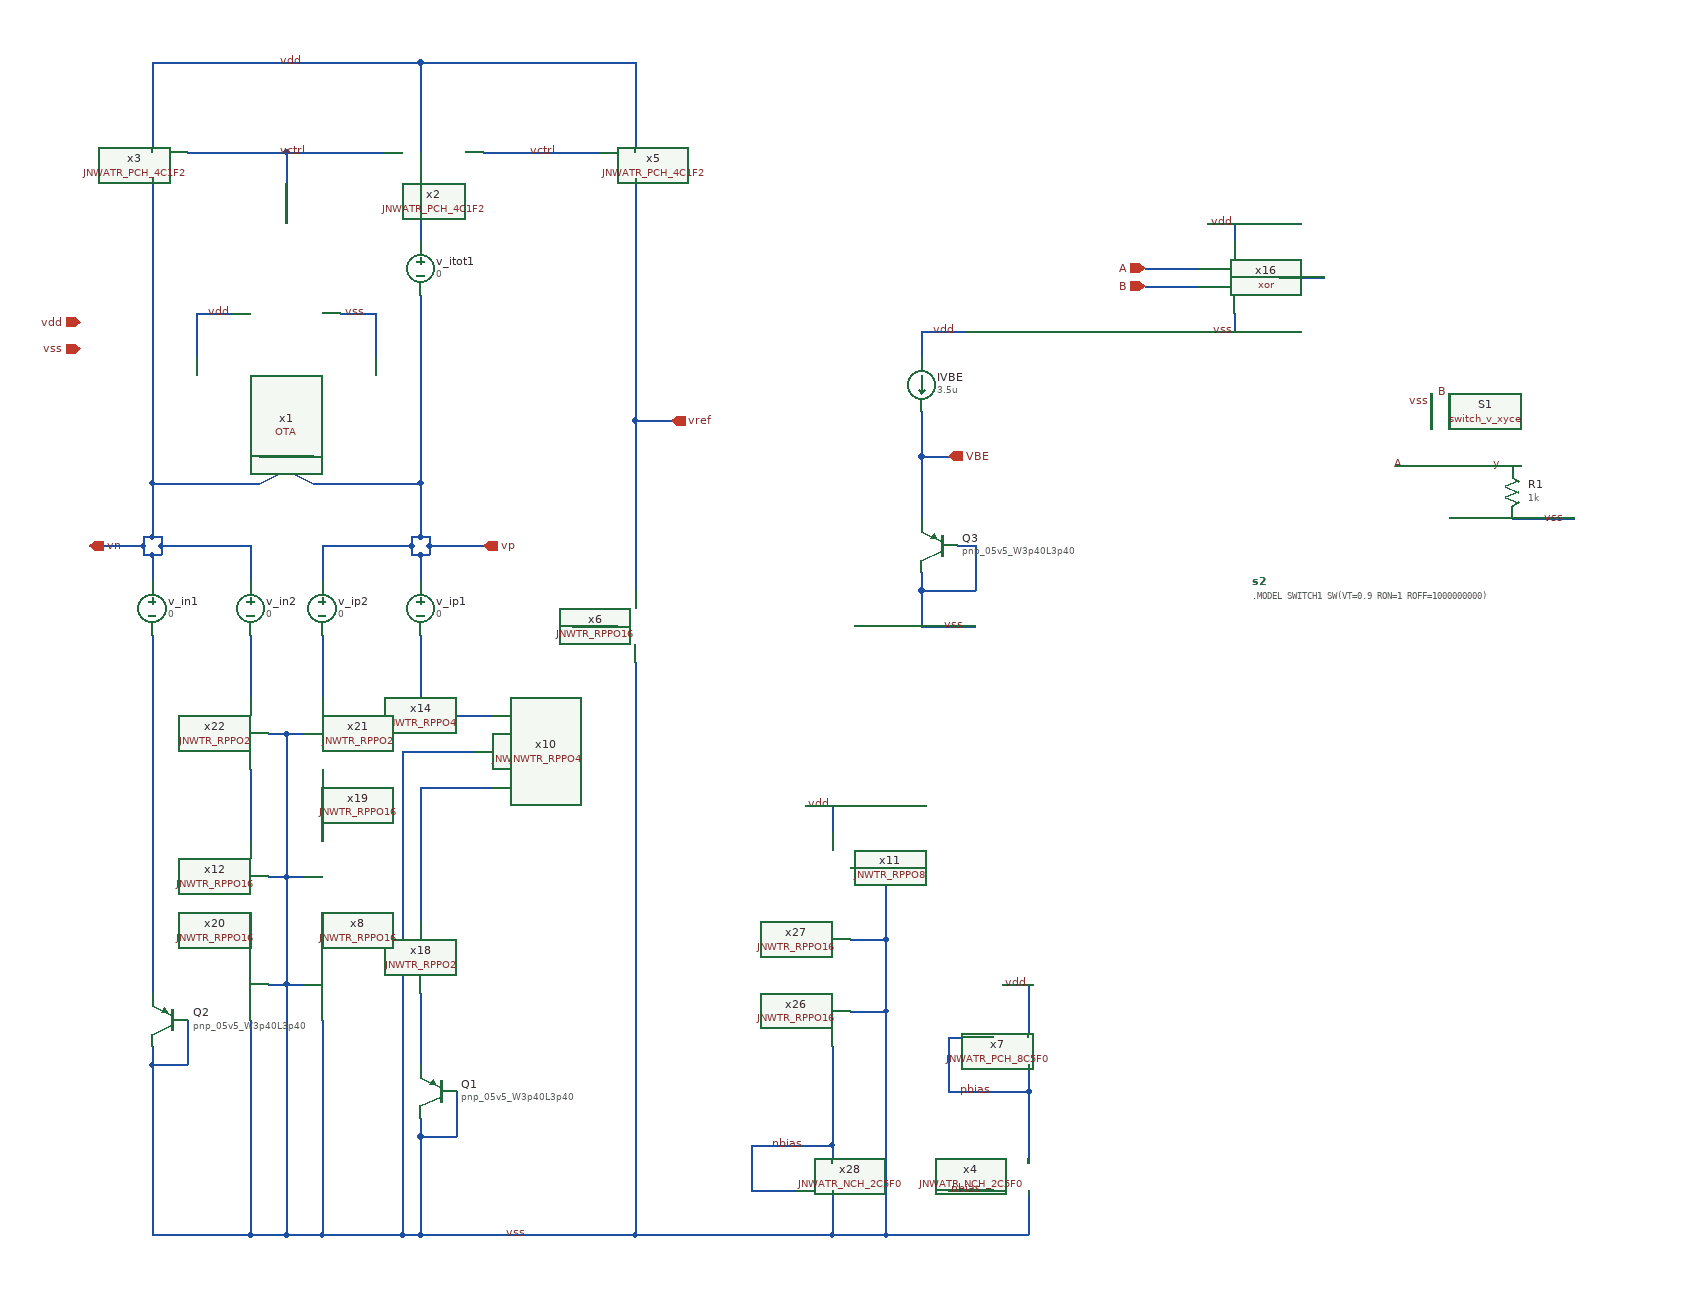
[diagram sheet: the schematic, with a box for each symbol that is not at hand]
v {xschem version=3.4.5 file_version=1.2
}
G {}
K {}
V {}
S {}
E {}
N 870 -120 960 -120 {
lab=nbias}
N 960 -120 960 -100 {
lab=nbias}
N 1180 -210 1180 -180 {
lab=pbias}
N 1090 -180 1180 -180 {
lab=pbias}
N 1090 -240 1090 -180 {
lab=pbias}
N 1090 -240 1140 -240 {
lab=pbias}
N 1180 -300 1180 -240 {
lab=vdd}
N 960 -70 960 -20 {
lab=vss}
N 930 -500 960 -500 {
lab=vdd}
N 1020 -270 1020 -20 {
lab=vss}
N 980 -270 1020 -270 {
lab=vss}
N 1020 -350 1020 -270 {
lab=vss}
N 980 -350 1020 -350 {
lab=vss}
N 1020 -430 1020 -350 {
lab=vss}
N 980 -430 1020 -430 {
lab=vss}
N 960 -500 960 -470 {
lab=vdd}
N 1090 -70 1140 -70 {
lab=nbias}
N 1020 -20 1180 -20 {
lab=vss}
N 1150 -300 1180 -300 {
lab=vdd}
N 870 -120 870 -70 {
lab=nbias}
N 870 -70 920 -70 {
lab=nbias}
N 1180 -70 1180 -20 {
lab=vss}
N 1180 -180 1180 -100 {
lab=pbias}
N 960 -230 960 -120 {
lab=nbias}
N 490 -790 490 -780 {
lab=vp}
N 500 -800 510 -800 {
lab=vp}
N 210 -790 210 -780 {
lab=vn}
N 200 -800 210 -800 {
lab=vn}
N 510 -790 510 -780 {
lab=vp}
N 210 -800 210 -790 {
lab=vn}
N 490 -800 490 -790 {
lab=vp}
N 390 -790 490 -790 {
lab=vp}
N 200 -780 210 -780 {
lab=vn}
N 210 -790 310 -790 {
lab=vn}
N 190 -790 190 -780 {
lab=vn}
N 240 -260 240 -210 {
lab=vss}
N 200 -210 240 -210 {
lab=vss}
N 200 -230 200 -210 {
lab=vss}
N 540 -180 540 -130 {
lab=vss}
N 500 -130 540 -130 {
lab=vss}
N 500 -150 500 -130 {
lab=vss}
N 500 -780 510 -780 {
lab=vp}
N 380 -860 500 -860 {
lab=vp}
N 200 -860 200 -800 {
lab=vn}
N 190 -800 200 -800 {
lab=vn}
N 500 -860 500 -800 {
lab=vp}
N 490 -800 500 -800 {
lab=vp}
N 200 -1200 200 -860 {
lab=vn}
N 200 -860 320 -860 {
lab=vn}
N 350 -1230 350 -1150 {
lab=vctrl}
N 350 -1230 460 -1230 {
lab=vctrl}
N 240 -1230 350 -1230 {
lab=vctrl}
N 200 -1330 200 -1230 {
lab=vdd}
N 200 -1330 500 -1330 {
lab=vdd}
N 740 -1330 740 -1230 {
lab=vdd}
N 500 -1330 740 -1330 {
lab=vdd}
N 500 -1330 500 -1230 {
lab=vdd}
N 740 -930 740 -740 {
lab=vref}
N 510 -790 570 -790 {
lab=vp}
N 510 -800 510 -790 {
lab=vp}
N 130 -790 190 -790 {
lab=vn}
N 190 -800 190 -790 {
lab=vn}
N 740 -930 780 -930 {
lab=vref}
N 740 -1200 740 -930 {
lab=vref}
N 570 -1230 700 -1230 {
lab=vctrl}
N 500 -130 500 -20 {
lab=vss}
N 200 -210 200 -20 {
lab=vss}
N 500 -20 740 -20 {
lab=vss}
N 670 -700 720 -700 {
lab=vss}
N 740 -660 740 -20 {
lab=vss}
N 960 -20 1020 -20 {
lab=vss}
N 740 -20 960 -20 {
lab=vss}
N 480 -20 500 -20 {
lab=vss}
N 500 -1200 500 -1130 {
lab=#net1}
N 500 -780 500 -750 {
lab=vp}
N 490 -780 500 -780 {
lab=vp}
N 390 -790 390 -750 {
lab=vp}
N 200 -780 200 -750 {
lab=vn}
N 190 -780 200 -780 {
lab=vn}
N 200 -690 200 -290 {
lab=#net2}
N 310 -790 310 -750 {
lab=vn}
N 1060 -890 1060 -820 {
lab=VBE}
N 1060 -740 1060 -700 {
lab=vss}
N 1060 -700 1120 -700 {
lab=vss}
N 1060 -1030 1060 -1000 {
lab=vdd}
N 1060 -1030 1110 -1030 {
lab=vdd}
N 1060 -890 1090 -890 {
lab=VBE}
N 1060 -940 1060 -890 {
lab=VBE}
N 1100 -790 1120 -790 {
lab=vss}
N 1120 -790 1120 -740 {
lab=vss}
N 1060 -740 1120 -740 {
lab=vss}
N 1060 -760 1060 -740 {
lab=vss}
N 1310 -1100 1370 -1100 {
lab=A}
N 1310 -1080 1370 -1080 {
lab=B}
N 1410 -1150 1410 -1130 {
lab=vdd}
N 1380 -1150 1410 -1150 {
lab=vdd}
N 1410 -1050 1410 -1030 {
lab=vss}
N 1380 -1030 1410 -1030 {
lab=vss}
N 1460 -1090 1510 -1090 {
lab=#net3}
N 500 -520 500 -370 {
lab=#net4}
N 350 -300 370 -300 {
lab=vss}
N 330 -300 350 -300 {
lab=vss}
N 310 -380 310 -340 {
lab=#net5}
N 390 -380 390 -340 {
lab=#net6}
N 350 -420 370 -420 {
lab=vss}
N 330 -420 350 -420 {
lab=vss}
N 350 -420 350 -300 {
lab=vss}
N 350 -580 370 -580 {
lab=vss}
N 350 -580 350 -420 {
lab=vss}
N 330 -580 350 -580 {
lab=vss}
N 390 -540 390 -460 {
lab=#net7}
N 310 -540 310 -460 {
lab=#net8}
N 500 -520 580 -520 {
lab=#net4}
N 500 -600 580 -600 {
lab=#net9}
N 480 -560 560 -560 {
lab=vss}
N 310 -690 310 -620 {
lab=#net10}
N 390 -690 390 -620 {
lab=#net11}
N 500 -690 500 -600 {
lab=#net9}
N 500 -290 500 -210 {
lab=#net12}
N 480 -560 480 -20 {
lab=vss}
N 390 -20 480 -20 {
lab=vss}
N 350 -300 350 -20 {
lab=vss}
N 310 -260 310 -20 {
lab=vss}
N 200 -20 310 -20 {
lab=vss}
N 390 -260 390 -20 {
lab=vss}
N 350 -20 390 -20 {
lab=vss}
N 310 -20 350 -20 {
lab=vss}
N 500 -1070 500 -860 {
lab=vp}
N 320 -860 380 -890 {
lab=vn}
N 320 -890 380 -860 {
lab=vp}
N 250 -1050 250 -1000 {
lab=vdd}
N 250 -1050 290 -1050 {
lab=vdd}
N 450 -1050 450 -1000 {
lab=vss}
N 410 -1050 450 -1050 {
lab=vss}
N 1680 -880 1720 -880 {
lab=y}
N 1630 -960 1630 -920 {
lab=vss}
N 1650 -960 1650 -920 {
lab=B}
N 1590 -880 1620 -880 {
lab=A}
N 1720 -820 1790 -820 {
lab=vss}
C {devices/ipin.sym} 120 -1010 0 0 {name=p4 lab=vss}
C {devices/ipin.sym} 120 -1040 0 0 {name=p5 lab=vdd}
C {devices/lab_wire.sym} 1140 -180 0 0 {name=p32 sig_type=std_logic lab=pbias}
C {devices/lab_wire.sym} 960 -500 0 0 {name=p34 sig_type=std_logic lab=vdd}
C {JNW_ATR_SKY130A/JNWATR_PCH_8C5F0.sym} 1140 -240 0 0 {name=x7 }
C {JNW_ATR_SKY130A/JNWATR_NCH_2C5F0.sym} 920 -70 0 0 {name=x28 }
C {devices/lab_wire.sym} 930 -120 0 0 {name=p12 sig_type=std_logic lab=nbias}
C {devices/lab_wire.sym} 1180 -300 0 0 {name=p13 sig_type=std_logic lab=vdd}
C {JNW_ATR_SKY130A/JNWATR_NCH_2C5F0.sym} 1140 -70 0 0 {name=x4 }
C {devices/lab_wire.sym} 1130 -70 0 0 {name=p14 sig_type=std_logic lab=nbias}
C {JNW_TR_SKY130A/JNWTR_RPPO16.sym} 960 -230 3 0 {name=x26 }
C {JNW_TR_SKY130A/JNWTR_RPPO16.sym} 960 -310 3 0 {name=x27 }
C {JNW_TR_SKY130A/JNWTR_RPPO8.sym} 960 -390 3 0 {name=x11 }
C {sky130_fd_pr/pnp_05v5.sym} 520 -180 0 1 {name=Q1
model=pnp_05v5_W3p40L3p40
m=8
spiceprefix=X
}
C {sky130_fd_pr/pnp_05v5.sym} 220 -260 0 1 {name=Q2
model=pnp_05v5_W3p40L3p40
m=1
spiceprefix=X
}
C {devices/lab_wire.sym} 340 -1330 0 1 {name=p29 sig_type=std_logic lab=vdd

}
C {devices/opin.sym} 130 -790 2 0 {name=p44 lab=vn}
C {JNW_ATR_SKY130A/JNWATR_PCH_4C1F2.sym} 460 -1230 0 0 {name=x2 }
C {JNW_ATR_SKY130A/JNWATR_PCH_4C1F2.sym} 240 -1230 0 1 {name=x3 }
C {JNW_ATR_SKY130A/JNWATR_PCH_4C1F2.sym} 700 -1230 0 0 {name=x5 }
C {devices/lab_wire.sym} 340 -1230 0 1 {name=p8 sig_type=std_logic lab=vctrl

}
C {devices/lab_wire.sym} 620 -1230 0 1 {name=p9 sig_type=std_logic lab=vctrl

}
C {devices/lab_wire.sym} 620 -20 0 0 {name=p3 sig_type=std_logic lab=vss
}
C {devices/opin.sym} 570 -790 0 0 {name=p7 lab=vp}
C {devices/opin.sym} 780 -930 0 0 {name=p10 lab=vref}
C {devices/lab_wire.sym} 700 -700 0 0 {name=p11 sig_type=std_logic lab=vss
}
C {JNW_TR_SKY130A/JNWTR_RPPO16.sym} 740 -740 1 0 {name=x6 }
C {devices/vsource.sym} 500 -1100 0 0 {name=v_itot1 value=0 savecurrent=true}
C {devices/vsource.sym} 500 -720 0 0 {name=v_ip1 value=0 savecurrent=true}
C {devices/vsource.sym} 390 -720 0 0 {name=v_ip2 value=0 savecurrent=true}
C {devices/vsource.sym} 200 -720 0 0 {name=v_in1 value=0 savecurrent=true}
C {devices/vsource.sym} 310 -720 0 0 {name=v_in2 value=0 savecurrent=true}
C {devices/isource.sym} 1060 -970 0 0 {name=IVBE value=3.5u}
C {devices/lab_wire.sym} 1100 -1030 0 0 {name=p15 sig_type=std_logic lab=vdd}
C {devices/lab_wire.sym} 1110 -700 0 0 {name=p16 sig_type=std_logic lab=vss
}
C {devices/opin.sym} 1090 -890 0 0 {name=p17 lab=VBE}
C {sky130_fd_pr/pnp_05v5.sym} 1080 -790 0 1 {name=Q3
model=pnp_05v5_W3p40L3p40
m=8
spiceprefix=X
}
C {devices/ipin.sym} 1310 -1080 0 0 {name=p18 lab=B}
C {devices/ipin.sym} 1310 -1100 0 0 {name=p19 lab=A}
C {JNW_AVV_SKY130A/xor.sym} 1410 -1090 0 0 {name=x16}
C {devices/lab_wire.sym} 1410 -1150 0 0 {name=p20 sig_type=std_logic lab=vdd}
C {devices/lab_wire.sym} 1410 -1030 0 0 {name=p21 sig_type=std_logic lab=vss
}
C {JNW_TR_SKY130A/JNWTR_RPPO2.sym} 500 -370 1 0 {name=x18 }
C {JNW_TR_SKY130A/JNWTR_RPPO16.sym} 390 -340 1 0 {name=x8 }
C {JNW_TR_SKY130A/JNWTR_RPPO16.sym} 310 -340 3 1 {name=x20 }
C {JNW_TR_SKY130A/JNWTR_RPPO4.sym} 540 -600 1 0 {name=x9 }
C {JNW_TR_SKY130A/JNWTR_RPPO4.sym} 500 -600 1 0 {name=x14 }
C {JNW_TR_SKY130A/JNWTR_RPPO4.sym} 580 -600 1 0 {name=x10 }
C {JNW_TR_SKY130A/JNWTR_RPPO16.sym} 310 -460 3 1 {name=x12 }
C {JNW_TR_SKY130A/JNWTR_RPPO16.sym} 390 -460 1 0 {name=x19 }
C {JNW_TR_SKY130A/JNWTR_RPPO2.sym} 390 -620 1 0 {name=x21 }
C {JNW_TR_SKY130A/JNWTR_RPPO2.sym} 310 -540 3 0 {name=x22 }
C {JNW_AVV_SKY130A/OTA.sym} 350 -1000 3 0 {name=x1}
C {devices/lab_wire.sym} 260 -1050 0 1 {name=p1 sig_type=std_logic lab=vdd

}
C {devices/lab_wire.sym} 440 -1050 0 0 {name=p2 sig_type=std_logic lab=vss
}
C {devices/lab_wire.sym} 1630 -950 0 0 {name=p6 sig_type=std_logic lab=vss
}
C {devices/lab_wire.sym} 1600 -880 0 0 {name=p23 sig_type=std_logic lab=A
}
C {devices/lab_wire.sym} 1650 -960 0 0 {name=p24 sig_type=std_logic lab=B
}
C {devices/lab_wire.sym} 1710 -880 0 0 {name=p25 sig_type=std_logic lab=y
}
C {devices/switch_v_xyce.sym} 1650 -880 1 0 {.MODEL SWITCH1 SW(VT=0.5 VH=0.01 RON=0.01 ROFF=10000000)

name=S1 model=SWITCH1 state=OFF

}
C {devices/netlist.sym} 1430 -750 0 0 {name=s2 value=".MODEL SWITCH1 SW(VT=0.9 RON=1 ROFF=1000000000)"
}
C {devices/res.sym} 1720 -850 0 0 {name=R1
value=1k
footprint=1206
device=resistor
m=1}
C {devices/lab_wire.sym} 1780 -820 0 0 {name=p22 sig_type=std_logic lab=vss
}
